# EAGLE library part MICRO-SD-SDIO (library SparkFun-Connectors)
microSD Socket for Transflash Push-push type µSD socket. tDoc lines correctly indicate media card edge positions when inserting (unlocked, locked, depressed). NOTE: CD1 and CD2 are connected internally, and the default detect state of the socket is detect pin to ground. SparkFun Products: WAV Trigger CAN-Bus Shield SparkFun Level Shifing microSD Breakout

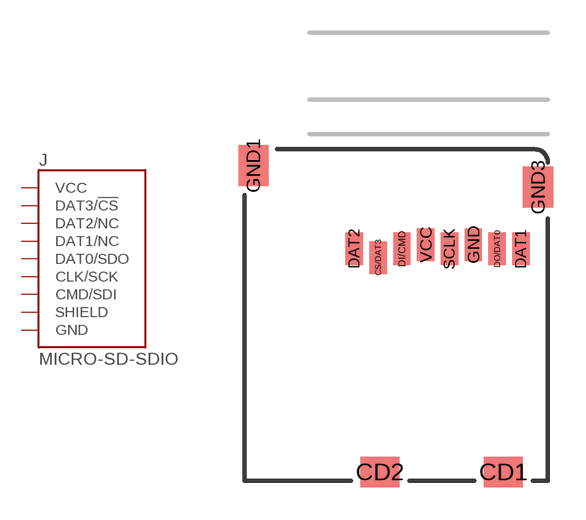
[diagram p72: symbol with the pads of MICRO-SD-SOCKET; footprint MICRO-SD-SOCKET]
Designator prefix J

## MICRO-SD-SDIOPUSH-PUSH (PROD_ID: CONN-07820)  [MICRO-SD-SOCKET]
CD1  SHIELD
CS/DAT3  DAT3/!CS!
DAT1  DAT1/NC
DAT2  DAT2/NC
DI/CMD  CMD/SDI
DO/DAT0  DAT0/SDO
GND  GND
GND1  GND
GND3  GND
SCLK  CLK/SCK
VCC  VCC

## Footprint MICRO-SD-SOCKET (pad centres in mm)
microSD Socket SMD Puhs-Push type. tDocu shows location of uSD card in different positions. Specifications: Pin count:12 Datasheet referenced for footprint Example device(s): MICRO-SD_CARD_SOCKET
smd 1.8 x 1.4: CD1 -2.05,0.4; CD2 -7.75,0.4
smd 0.8 x 1.5: CS/DAT3 -7.84,10.3; DAT1 -1.24,10.7; DAT2 -8.94,10.7; DI/CMD -6.74,10.7; DO/DAT0 -2.34,10.7; GND -3.44,10.9; SCLK -4.54,10.7; VCC -5.64,10.9
smd 1.4 x 1.9: GND1 -13.6,14.55; GND3 -0.45,13.55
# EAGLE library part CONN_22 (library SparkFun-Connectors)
Standard 22-pin 0.1" header

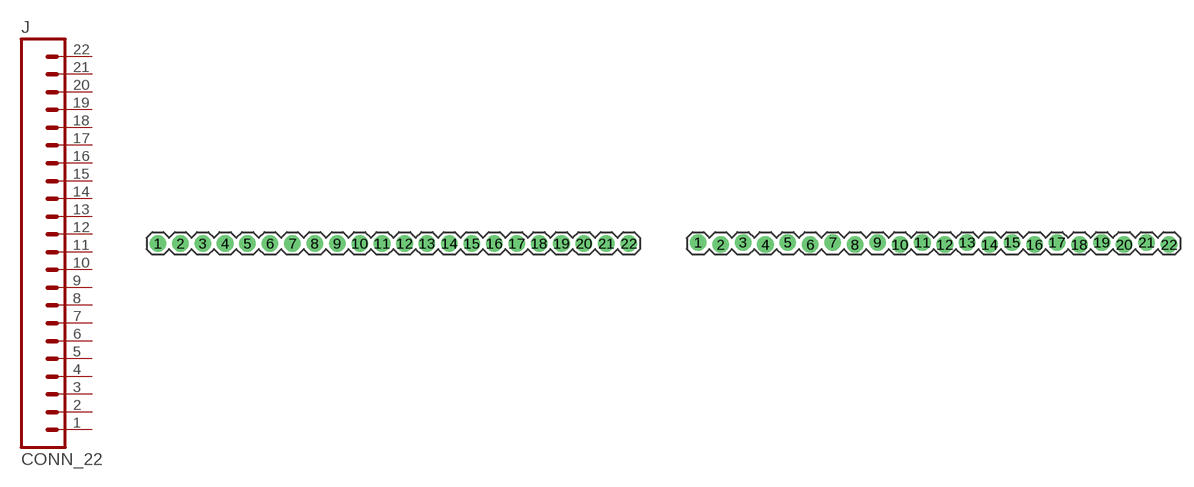
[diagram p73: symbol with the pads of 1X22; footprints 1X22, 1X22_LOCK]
Designator prefix J

## CONN_22_PTH (PROD_ID: CONN-13453)  [1X22]
1  1  pas
2  2  pas
3  3  pas
4  4  pas
5  5  pas
6  6  pas
7  7  pas
8  8  pas
9  9  pas
10  10  pas
11  11  pas
12  12  pas
13  13  pas
14  14  pas
15  15  pas
16  16  pas
17  17  pas
18  18  pas
19  19  pas
20  20  pas
21  21  pas
22  22  pas

## CONN_22_LOCK (PROD_ID: CONN-13453)  [1X22_LOCK]
Pads as for 1X22

## CONN_22_NOSILK (PROD_ID: CONN-13453)  [1X22_NOSILK]
Pads as for 1X22

## Footprint 1X22 (pad centres in mm)
drill 1.016 pad 1.88: 1 0,0; 2 2.54,0; 3 5.08,0; 4 7.62,0; 5 10.16,0; 6 12.7,0; 7 15.24,0; 8 17.78,0; 9 20.32,0; 10 22.86,0; 11 25.4,0; 12 27.94,0; 13 30.48,0; 14 33.02,0; 15 35.56,0; 16 38.1,0; 17 40.64,0; 18 43.18,0; 19 45.72,0; 20 48.26,0; 21 50.8,0; 22 53.34,0

## Footprint 1X22_LOCK (pad centres in mm)
drill 1.016 pad 1.88: 1 0,0.127; 2 2.54,-0.127; 3 5.08,0.127; 4 7.62,-0.127; 5 10.16,0.127; 6 12.7,-0.127; 7 15.24,0.127; 8 17.78,-0.127; 9 20.32,0.127; 10 22.86,-0.127; 11 25.4,0.127; 12 27.94,-0.127; 13 30.48,0.127; 14 33.02,-0.127; 15 35.56,0.127; 16 38.1,-0.127; 17 40.64,0.127; 18 43.18,-0.127; 19 45.72,0.127; 20 48.26,-0.127; 21 50.8,0.127; 22 53.34,-0.127

## Footprint 1X22_NOSILK (pad centres in mm)
drill 1.016 pad 1.88: 1 0,0; 2 2.54,0; 3 5.08,0; 4 7.62,0; 5 10.16,0; 6 12.7,0; 7 15.24,0; 8 17.78,0; 9 20.32,0; 10 22.86,0; 11 25.4,0; 12 27.94,0; 13 30.48,0; 14 33.02,0; 15 35.56,0; 16 38.1,0; 17 40.64,0; 18 43.18,0; 19 45.72,0; 20 48.26,0; 21 50.8,0; 22 53.34,0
